VERSION 5.7 ;
  NOWIREEXTENSIONATPIN ON ;
  DIVIDERCHAR "/" ;
  BUSBITCHARS "[]" ;
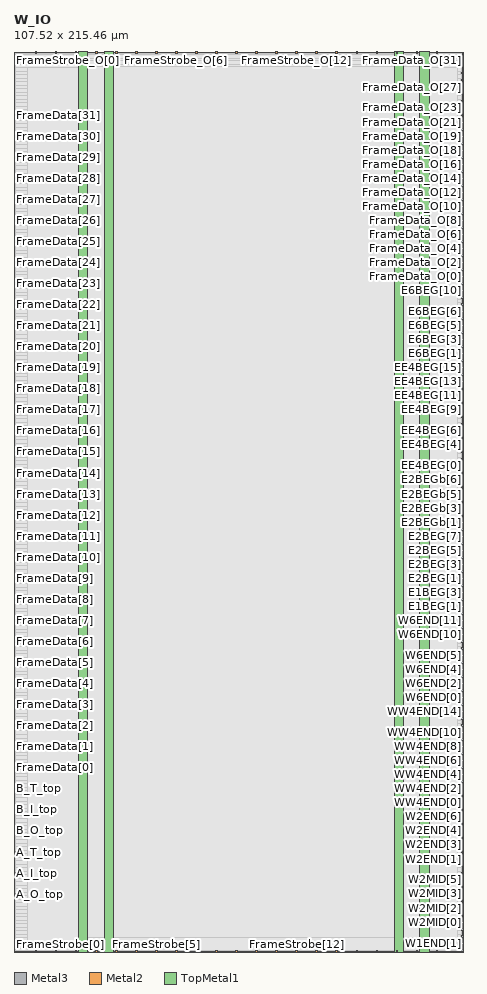
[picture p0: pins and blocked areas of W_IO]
MACRO W_IO
  CLASS BLOCK ;
  FOREIGN W_IO ;
  ORIGIN 0.000 0.000 ;
  SIZE 107.520 BY 215.460 ;
  PIN A_I_top
    DIRECTION OUTPUT ;
    USE SIGNAL ;
    ANTENNADIFFAREA 0.708600 ;
    PORT
      LAYER Metal3 ;
        RECT 0.000 18.700 0.400 19.100 ;
    END
  END A_I_top
  PIN A_O_top
    DIRECTION INPUT ;
    USE SIGNAL ;
    ANTENNAGATEAREA 0.213200 ;
    PORT
      LAYER Metal3 ;
        RECT 0.000 13.660 0.400 14.060 ;
    END
  END A_O_top
  PIN A_T_top
    DIRECTION OUTPUT ;
    USE SIGNAL ;
    ANTENNADIFFAREA 0.708600 ;
    PORT
      LAYER Metal3 ;
        RECT 0.000 23.740 0.400 24.140 ;
    END
  END A_T_top
  PIN B_I_top
    DIRECTION OUTPUT ;
    USE SIGNAL ;
    ANTENNADIFFAREA 0.708600 ;
    PORT
      LAYER Metal3 ;
        RECT 0.000 33.820 0.400 34.220 ;
    END
  END B_I_top
  PIN B_O_top
    DIRECTION INPUT ;
    USE SIGNAL ;
    ANTENNAGATEAREA 0.213200 ;
    PORT
      LAYER Metal3 ;
        RECT 0.000 28.780 0.400 29.180 ;
    END
  END B_O_top
  PIN B_T_top
    DIRECTION OUTPUT ;
    USE SIGNAL ;
    ANTENNADIFFAREA 0.708600 ;
    PORT
      LAYER Metal3 ;
        RECT 0.000 38.860 0.400 39.260 ;
    END
  END B_T_top
  PIN E1BEG[0]
    DIRECTION OUTPUT ;
    USE SIGNAL ;
    ANTENNADIFFAREA 0.708600 ;
    PORT
      LAYER Metal3 ;
        RECT 107.120 80.860 107.520 81.260 ;
    END
  END E1BEG[0]
  PIN E1BEG[1]
    DIRECTION OUTPUT ;
    USE SIGNAL ;
    ANTENNADIFFAREA 0.708600 ;
    PORT
      LAYER Metal3 ;
        RECT 107.120 82.540 107.520 82.940 ;
    END
  END E1BEG[1]
  PIN E1BEG[2]
    DIRECTION OUTPUT ;
    USE SIGNAL ;
    ANTENNADIFFAREA 0.708600 ;
    PORT
      LAYER Metal3 ;
        RECT 107.120 84.220 107.520 84.620 ;
    END
  END E1BEG[2]
  PIN E1BEG[3]
    DIRECTION OUTPUT ;
    USE SIGNAL ;
    ANTENNADIFFAREA 0.708600 ;
    PORT
      LAYER Metal3 ;
        RECT 107.120 85.900 107.520 86.300 ;
    END
  END E1BEG[3]
  PIN E2BEG[0]
    DIRECTION OUTPUT ;
    USE SIGNAL ;
    ANTENNADIFFAREA 0.708600 ;
    PORT
      LAYER Metal3 ;
        RECT 107.120 87.580 107.520 87.980 ;
    END
  END E2BEG[0]
  PIN E2BEG[1]
    DIRECTION OUTPUT ;
    USE SIGNAL ;
    ANTENNADIFFAREA 0.708600 ;
    PORT
      LAYER Metal3 ;
        RECT 107.120 89.260 107.520 89.660 ;
    END
  END E2BEG[1]
  PIN E2BEG[2]
    DIRECTION OUTPUT ;
    USE SIGNAL ;
    ANTENNADIFFAREA 0.708600 ;
    PORT
      LAYER Metal3 ;
        RECT 107.120 90.940 107.520 91.340 ;
    END
  END E2BEG[2]
  PIN E2BEG[3]
    DIRECTION OUTPUT ;
    USE SIGNAL ;
    ANTENNADIFFAREA 0.708600 ;
    PORT
      LAYER Metal3 ;
        RECT 107.120 92.620 107.520 93.020 ;
    END
  END E2BEG[3]
  PIN E2BEG[4]
    DIRECTION OUTPUT ;
    USE SIGNAL ;
    ANTENNADIFFAREA 0.708600 ;
    PORT
      LAYER Metal3 ;
        RECT 107.120 94.300 107.520 94.700 ;
    END
  END E2BEG[4]
  PIN E2BEG[5]
    DIRECTION OUTPUT ;
    USE SIGNAL ;
    ANTENNADIFFAREA 0.708600 ;
    PORT
      LAYER Metal3 ;
        RECT 107.120 95.980 107.520 96.380 ;
    END
  END E2BEG[5]
  PIN E2BEG[6]
    DIRECTION OUTPUT ;
    USE SIGNAL ;
    ANTENNADIFFAREA 0.708600 ;
    PORT
      LAYER Metal3 ;
        RECT 107.120 97.660 107.520 98.060 ;
    END
  END E2BEG[6]
  PIN E2BEG[7]
    DIRECTION OUTPUT ;
    USE SIGNAL ;
    ANTENNADIFFAREA 0.708600 ;
    PORT
      LAYER Metal3 ;
        RECT 107.120 99.340 107.520 99.740 ;
    END
  END E2BEG[7]
  PIN E2BEGb[0]
    DIRECTION OUTPUT ;
    USE SIGNAL ;
    ANTENNADIFFAREA 0.708600 ;
    PORT
      LAYER Metal3 ;
        RECT 107.120 101.020 107.520 101.420 ;
    END
  END E2BEGb[0]
  PIN E2BEGb[1]
    DIRECTION OUTPUT ;
    USE SIGNAL ;
    ANTENNADIFFAREA 0.708600 ;
    PORT
      LAYER Metal3 ;
        RECT 107.120 102.700 107.520 103.100 ;
    END
  END E2BEGb[1]
  PIN E2BEGb[2]
    DIRECTION OUTPUT ;
    USE SIGNAL ;
    ANTENNADIFFAREA 0.708600 ;
    PORT
      LAYER Metal3 ;
        RECT 107.120 104.380 107.520 104.780 ;
    END
  END E2BEGb[2]
  PIN E2BEGb[3]
    DIRECTION OUTPUT ;
    USE SIGNAL ;
    ANTENNADIFFAREA 0.708600 ;
    PORT
      LAYER Metal3 ;
        RECT 107.120 106.060 107.520 106.460 ;
    END
  END E2BEGb[3]
  PIN E2BEGb[4]
    DIRECTION OUTPUT ;
    USE SIGNAL ;
    ANTENNADIFFAREA 0.708600 ;
    PORT
      LAYER Metal3 ;
        RECT 107.120 107.740 107.520 108.140 ;
    END
  END E2BEGb[4]
  PIN E2BEGb[5]
    DIRECTION OUTPUT ;
    USE SIGNAL ;
    ANTENNADIFFAREA 0.708600 ;
    PORT
      LAYER Metal3 ;
        RECT 107.120 109.420 107.520 109.820 ;
    END
  END E2BEGb[5]
  PIN E2BEGb[6]
    DIRECTION OUTPUT ;
    USE SIGNAL ;
    ANTENNADIFFAREA 0.708600 ;
    PORT
      LAYER Metal3 ;
        RECT 107.120 111.100 107.520 111.500 ;
    END
  END E2BEGb[6]
  PIN E2BEGb[7]
    DIRECTION OUTPUT ;
    USE SIGNAL ;
    ANTENNADIFFAREA 0.708600 ;
    PORT
      LAYER Metal3 ;
        RECT 107.120 112.780 107.520 113.180 ;
    END
  END E2BEGb[7]
  PIN E6BEG[0]
    DIRECTION OUTPUT ;
    USE SIGNAL ;
    ANTENNADIFFAREA 0.708600 ;
    PORT
      LAYER Metal3 ;
        RECT 107.120 141.340 107.520 141.740 ;
    END
  END E6BEG[0]
  PIN E6BEG[10]
    DIRECTION OUTPUT ;
    USE SIGNAL ;
    ANTENNADIFFAREA 0.708600 ;
    PORT
      LAYER Metal3 ;
        RECT 107.120 158.140 107.520 158.540 ;
    END
  END E6BEG[10]
  PIN E6BEG[11]
    DIRECTION OUTPUT ;
    USE SIGNAL ;
    ANTENNADIFFAREA 0.708600 ;
    PORT
      LAYER Metal3 ;
        RECT 107.120 159.820 107.520 160.220 ;
    END
  END E6BEG[11]
  PIN E6BEG[1]
    DIRECTION OUTPUT ;
    USE SIGNAL ;
    ANTENNADIFFAREA 0.708600 ;
    PORT
      LAYER Metal3 ;
        RECT 107.120 143.020 107.520 143.420 ;
    END
  END E6BEG[1]
  PIN E6BEG[2]
    DIRECTION OUTPUT ;
    USE SIGNAL ;
    ANTENNADIFFAREA 0.708600 ;
    PORT
      LAYER Metal3 ;
        RECT 107.120 144.700 107.520 145.100 ;
    END
  END E6BEG[2]
  PIN E6BEG[3]
    DIRECTION OUTPUT ;
    USE SIGNAL ;
    ANTENNADIFFAREA 0.708600 ;
    PORT
      LAYER Metal3 ;
        RECT 107.120 146.380 107.520 146.780 ;
    END
  END E6BEG[3]
  PIN E6BEG[4]
    DIRECTION OUTPUT ;
    USE SIGNAL ;
    ANTENNADIFFAREA 0.708600 ;
    PORT
      LAYER Metal3 ;
        RECT 107.120 148.060 107.520 148.460 ;
    END
  END E6BEG[4]
  PIN E6BEG[5]
    DIRECTION OUTPUT ;
    USE SIGNAL ;
    ANTENNADIFFAREA 0.708600 ;
    PORT
      LAYER Metal3 ;
        RECT 107.120 149.740 107.520 150.140 ;
    END
  END E6BEG[5]
  PIN E6BEG[6]
    DIRECTION OUTPUT ;
    USE SIGNAL ;
    ANTENNADIFFAREA 0.708600 ;
    PORT
      LAYER Metal3 ;
        RECT 107.120 151.420 107.520 151.820 ;
    END
  END E6BEG[6]
  PIN E6BEG[7]
    DIRECTION OUTPUT ;
    USE SIGNAL ;
    ANTENNADIFFAREA 0.708600 ;
    PORT
      LAYER Metal3 ;
        RECT 107.120 153.100 107.520 153.500 ;
    END
  END E6BEG[7]
  PIN E6BEG[8]
    DIRECTION OUTPUT ;
    USE SIGNAL ;
    ANTENNADIFFAREA 0.708600 ;
    PORT
      LAYER Metal3 ;
        RECT 107.120 154.780 107.520 155.180 ;
    END
  END E6BEG[8]
  PIN E6BEG[9]
    DIRECTION OUTPUT ;
    USE SIGNAL ;
    ANTENNADIFFAREA 0.708600 ;
    PORT
      LAYER Metal3 ;
        RECT 107.120 156.460 107.520 156.860 ;
    END
  END E6BEG[9]
  PIN EE4BEG[0]
    DIRECTION OUTPUT ;
    USE SIGNAL ;
    ANTENNADIFFAREA 0.708600 ;
    PORT
      LAYER Metal3 ;
        RECT 107.120 114.460 107.520 114.860 ;
    END
  END EE4BEG[0]
  PIN EE4BEG[10]
    DIRECTION OUTPUT ;
    USE SIGNAL ;
    ANTENNADIFFAREA 0.708600 ;
    PORT
      LAYER Metal3 ;
        RECT 107.120 131.260 107.520 131.660 ;
    END
  END EE4BEG[10]
  PIN EE4BEG[11]
    DIRECTION OUTPUT ;
    USE SIGNAL ;
    ANTENNADIFFAREA 0.708600 ;
    PORT
      LAYER Metal3 ;
        RECT 107.120 132.940 107.520 133.340 ;
    END
  END EE4BEG[11]
  PIN EE4BEG[12]
    DIRECTION OUTPUT ;
    USE SIGNAL ;
    ANTENNADIFFAREA 0.708600 ;
    PORT
      LAYER Metal3 ;
        RECT 107.120 134.620 107.520 135.020 ;
    END
  END EE4BEG[12]
  PIN EE4BEG[13]
    DIRECTION OUTPUT ;
    USE SIGNAL ;
    ANTENNADIFFAREA 0.708600 ;
    PORT
      LAYER Metal3 ;
        RECT 107.120 136.300 107.520 136.700 ;
    END
  END EE4BEG[13]
  PIN EE4BEG[14]
    DIRECTION OUTPUT ;
    USE SIGNAL ;
    ANTENNADIFFAREA 0.708600 ;
    PORT
      LAYER Metal3 ;
        RECT 107.120 137.980 107.520 138.380 ;
    END
  END EE4BEG[14]
  PIN EE4BEG[15]
    DIRECTION OUTPUT ;
    USE SIGNAL ;
    ANTENNADIFFAREA 0.708600 ;
    PORT
      LAYER Metal3 ;
        RECT 107.120 139.660 107.520 140.060 ;
    END
  END EE4BEG[15]
  PIN EE4BEG[1]
    DIRECTION OUTPUT ;
    USE SIGNAL ;
    ANTENNADIFFAREA 0.708600 ;
    PORT
      LAYER Metal3 ;
        RECT 107.120 116.140 107.520 116.540 ;
    END
  END EE4BEG[1]
  PIN EE4BEG[2]
    DIRECTION OUTPUT ;
    USE SIGNAL ;
    ANTENNADIFFAREA 0.708600 ;
    PORT
      LAYER Metal3 ;
        RECT 107.120 117.820 107.520 118.220 ;
    END
  END EE4BEG[2]
  PIN EE4BEG[3]
    DIRECTION OUTPUT ;
    USE SIGNAL ;
    ANTENNADIFFAREA 0.708600 ;
    PORT
      LAYER Metal3 ;
        RECT 107.120 119.500 107.520 119.900 ;
    END
  END EE4BEG[3]
  PIN EE4BEG[4]
    DIRECTION OUTPUT ;
    USE SIGNAL ;
    ANTENNADIFFAREA 0.708600 ;
    PORT
      LAYER Metal3 ;
        RECT 107.120 121.180 107.520 121.580 ;
    END
  END EE4BEG[4]
  PIN EE4BEG[5]
    DIRECTION OUTPUT ;
    USE SIGNAL ;
    ANTENNADIFFAREA 0.708600 ;
    PORT
      LAYER Metal3 ;
        RECT 107.120 122.860 107.520 123.260 ;
    END
  END EE4BEG[5]
  PIN EE4BEG[6]
    DIRECTION OUTPUT ;
    USE SIGNAL ;
    ANTENNADIFFAREA 0.708600 ;
    PORT
      LAYER Metal3 ;
        RECT 107.120 124.540 107.520 124.940 ;
    END
  END EE4BEG[6]
  PIN EE4BEG[7]
    DIRECTION OUTPUT ;
    USE SIGNAL ;
    ANTENNADIFFAREA 0.708600 ;
    PORT
      LAYER Metal3 ;
        RECT 107.120 126.220 107.520 126.620 ;
    END
  END EE4BEG[7]
  PIN EE4BEG[8]
    DIRECTION OUTPUT ;
    USE SIGNAL ;
    ANTENNADIFFAREA 0.708600 ;
    PORT
      LAYER Metal3 ;
        RECT 107.120 127.900 107.520 128.300 ;
    END
  END EE4BEG[8]
  PIN EE4BEG[9]
    DIRECTION OUTPUT ;
    USE SIGNAL ;
    ANTENNADIFFAREA 0.708600 ;
    PORT
      LAYER Metal3 ;
        RECT 107.120 129.580 107.520 129.980 ;
    END
  END EE4BEG[9]
  PIN FrameData[0]
    DIRECTION INPUT ;
    USE SIGNAL ;
    ANTENNAGATEAREA 0.180700 ;
    PORT
      LAYER Metal3 ;
        RECT 0.000 43.900 0.400 44.300 ;
    END
  END FrameData[0]
  PIN FrameData[10]
    DIRECTION INPUT ;
    USE SIGNAL ;
    ANTENNAGATEAREA 0.180700 ;
    PORT
      LAYER Metal3 ;
        RECT 0.000 94.300 0.400 94.700 ;
    END
  END FrameData[10]
  PIN FrameData[11]
    DIRECTION INPUT ;
    USE SIGNAL ;
    ANTENNAGATEAREA 0.180700 ;
    PORT
      LAYER Metal3 ;
        RECT 0.000 99.340 0.400 99.740 ;
    END
  END FrameData[11]
  PIN FrameData[12]
    DIRECTION INPUT ;
    USE SIGNAL ;
    ANTENNAGATEAREA 0.180700 ;
    PORT
      LAYER Metal3 ;
        RECT 0.000 104.380 0.400 104.780 ;
    END
  END FrameData[12]
  PIN FrameData[13]
    DIRECTION INPUT ;
    USE SIGNAL ;
    ANTENNAGATEAREA 0.180700 ;
    PORT
      LAYER Metal3 ;
        RECT 0.000 109.420 0.400 109.820 ;
    END
  END FrameData[13]
  PIN FrameData[14]
    DIRECTION INPUT ;
    USE SIGNAL ;
    ANTENNAGATEAREA 0.180700 ;
    PORT
      LAYER Metal3 ;
        RECT 0.000 114.460 0.400 114.860 ;
    END
  END FrameData[14]
  PIN FrameData[15]
    DIRECTION INPUT ;
    USE SIGNAL ;
    ANTENNAGATEAREA 0.180700 ;
    PORT
      LAYER Metal3 ;
        RECT 0.000 119.500 0.400 119.900 ;
    END
  END FrameData[15]
  PIN FrameData[16]
    DIRECTION INPUT ;
    USE SIGNAL ;
    ANTENNAGATEAREA 0.180700 ;
    PORT
      LAYER Metal3 ;
        RECT 0.000 124.540 0.400 124.940 ;
    END
  END FrameData[16]
  PIN FrameData[17]
    DIRECTION INPUT ;
    USE SIGNAL ;
    ANTENNAGATEAREA 0.180700 ;
    PORT
      LAYER Metal3 ;
        RECT 0.000 129.580 0.400 129.980 ;
    END
  END FrameData[17]
  PIN FrameData[18]
    DIRECTION INPUT ;
    USE SIGNAL ;
    ANTENNAGATEAREA 0.180700 ;
    PORT
      LAYER Metal3 ;
        RECT 0.000 134.620 0.400 135.020 ;
    END
  END FrameData[18]
  PIN FrameData[19]
    DIRECTION INPUT ;
    USE SIGNAL ;
    ANTENNAGATEAREA 0.180700 ;
    PORT
      LAYER Metal3 ;
        RECT 0.000 139.660 0.400 140.060 ;
    END
  END FrameData[19]
  PIN FrameData[1]
    DIRECTION INPUT ;
    USE SIGNAL ;
    ANTENNAGATEAREA 0.180700 ;
    PORT
      LAYER Metal3 ;
        RECT 0.000 48.940 0.400 49.340 ;
    END
  END FrameData[1]
  PIN FrameData[20]
    DIRECTION INPUT ;
    USE SIGNAL ;
    ANTENNAGATEAREA 0.180700 ;
    PORT
      LAYER Metal3 ;
        RECT 0.000 144.700 0.400 145.100 ;
    END
  END FrameData[20]
  PIN FrameData[21]
    DIRECTION INPUT ;
    USE SIGNAL ;
    ANTENNAGATEAREA 0.180700 ;
    PORT
      LAYER Metal3 ;
        RECT 0.000 149.740 0.400 150.140 ;
    END
  END FrameData[21]
  PIN FrameData[22]
    DIRECTION INPUT ;
    USE SIGNAL ;
    ANTENNAGATEAREA 0.213200 ;
    PORT
      LAYER Metal3 ;
        RECT 0.000 154.780 0.400 155.180 ;
    END
  END FrameData[22]
  PIN FrameData[23]
    DIRECTION INPUT ;
    USE SIGNAL ;
    ANTENNAGATEAREA 0.213200 ;
    PORT
      LAYER Metal3 ;
        RECT 0.000 159.820 0.400 160.220 ;
    END
  END FrameData[23]
  PIN FrameData[24]
    DIRECTION INPUT ;
    USE SIGNAL ;
    ANTENNAGATEAREA 0.213200 ;
    PORT
      LAYER Metal3 ;
        RECT 0.000 164.860 0.400 165.260 ;
    END
  END FrameData[24]
  PIN FrameData[25]
    DIRECTION INPUT ;
    USE SIGNAL ;
    ANTENNAGATEAREA 0.213200 ;
    PORT
      LAYER Metal3 ;
        RECT 0.000 169.900 0.400 170.300 ;
    END
  END FrameData[25]
  PIN FrameData[26]
    DIRECTION INPUT ;
    USE SIGNAL ;
    ANTENNAGATEAREA 0.213200 ;
    PORT
      LAYER Metal3 ;
        RECT 0.000 174.940 0.400 175.340 ;
    END
  END FrameData[26]
  PIN FrameData[27]
    DIRECTION INPUT ;
    USE SIGNAL ;
    ANTENNAGATEAREA 0.213200 ;
    PORT
      LAYER Metal3 ;
        RECT 0.000 179.980 0.400 180.380 ;
    END
  END FrameData[27]
  PIN FrameData[28]
    DIRECTION INPUT ;
    USE SIGNAL ;
    ANTENNAGATEAREA 0.213200 ;
    PORT
      LAYER Metal3 ;
        RECT 0.000 185.020 0.400 185.420 ;
    END
  END FrameData[28]
  PIN FrameData[29]
    DIRECTION INPUT ;
    USE SIGNAL ;
    ANTENNAGATEAREA 0.213200 ;
    PORT
      LAYER Metal3 ;
        RECT 0.000 190.060 0.400 190.460 ;
    END
  END FrameData[29]
  PIN FrameData[2]
    DIRECTION INPUT ;
    USE SIGNAL ;
    ANTENNAGATEAREA 0.180700 ;
    PORT
      LAYER Metal3 ;
        RECT 0.000 53.980 0.400 54.380 ;
    END
  END FrameData[2]
  PIN FrameData[30]
    DIRECTION INPUT ;
    USE SIGNAL ;
    ANTENNAGATEAREA 0.213200 ;
    PORT
      LAYER Metal3 ;
        RECT 0.000 195.100 0.400 195.500 ;
    END
  END FrameData[30]
  PIN FrameData[31]
    DIRECTION INPUT ;
    USE SIGNAL ;
    ANTENNAGATEAREA 0.213200 ;
    PORT
      LAYER Metal3 ;
        RECT 0.000 200.140 0.400 200.540 ;
    END
  END FrameData[31]
  PIN FrameData[3]
    DIRECTION INPUT ;
    USE SIGNAL ;
    ANTENNAGATEAREA 0.180700 ;
    PORT
      LAYER Metal3 ;
        RECT 0.000 59.020 0.400 59.420 ;
    END
  END FrameData[3]
  PIN FrameData[4]
    DIRECTION INPUT ;
    USE SIGNAL ;
    ANTENNAGATEAREA 0.180700 ;
    PORT
      LAYER Metal3 ;
        RECT 0.000 64.060 0.400 64.460 ;
    END
  END FrameData[4]
  PIN FrameData[5]
    DIRECTION INPUT ;
    USE SIGNAL ;
    ANTENNAGATEAREA 0.180700 ;
    PORT
      LAYER Metal3 ;
        RECT 0.000 69.100 0.400 69.500 ;
    END
  END FrameData[5]
  PIN FrameData[6]
    DIRECTION INPUT ;
    USE SIGNAL ;
    ANTENNAGATEAREA 0.180700 ;
    PORT
      LAYER Metal3 ;
        RECT 0.000 74.140 0.400 74.540 ;
    END
  END FrameData[6]
  PIN FrameData[7]
    DIRECTION INPUT ;
    USE SIGNAL ;
    ANTENNAGATEAREA 0.180700 ;
    PORT
      LAYER Metal3 ;
        RECT 0.000 79.180 0.400 79.580 ;
    END
  END FrameData[7]
  PIN FrameData[8]
    DIRECTION INPUT ;
    USE SIGNAL ;
    ANTENNAGATEAREA 0.180700 ;
    PORT
      LAYER Metal3 ;
        RECT 0.000 84.220 0.400 84.620 ;
    END
  END FrameData[8]
  PIN FrameData[9]
    DIRECTION INPUT ;
    USE SIGNAL ;
    ANTENNAGATEAREA 0.180700 ;
    PORT
      LAYER Metal3 ;
        RECT 0.000 89.260 0.400 89.660 ;
    END
  END FrameData[9]
  PIN FrameData_O[0]
    DIRECTION OUTPUT ;
    USE SIGNAL ;
    ANTENNADIFFAREA 0.708600 ;
    PORT
      LAYER Metal3 ;
        RECT 107.120 161.500 107.520 161.900 ;
    END
  END FrameData_O[0]
  PIN FrameData_O[10]
    DIRECTION OUTPUT ;
    USE SIGNAL ;
    ANTENNADIFFAREA 0.708600 ;
    PORT
      LAYER Metal3 ;
        RECT 107.120 178.300 107.520 178.700 ;
    END
  END FrameData_O[10]
  PIN FrameData_O[11]
    DIRECTION OUTPUT ;
    USE SIGNAL ;
    ANTENNADIFFAREA 0.708600 ;
    PORT
      LAYER Metal3 ;
        RECT 107.120 179.980 107.520 180.380 ;
    END
  END FrameData_O[11]
  PIN FrameData_O[12]
    DIRECTION OUTPUT ;
    USE SIGNAL ;
    ANTENNADIFFAREA 0.708600 ;
    PORT
      LAYER Metal3 ;
        RECT 107.120 181.660 107.520 182.060 ;
    END
  END FrameData_O[12]
  PIN FrameData_O[13]
    DIRECTION OUTPUT ;
    USE SIGNAL ;
    ANTENNADIFFAREA 0.708600 ;
    PORT
      LAYER Metal3 ;
        RECT 107.120 183.340 107.520 183.740 ;
    END
  END FrameData_O[13]
  PIN FrameData_O[14]
    DIRECTION OUTPUT ;
    USE SIGNAL ;
    ANTENNADIFFAREA 0.708600 ;
    PORT
      LAYER Metal3 ;
        RECT 107.120 185.020 107.520 185.420 ;
    END
  END FrameData_O[14]
  PIN FrameData_O[15]
    DIRECTION OUTPUT ;
    USE SIGNAL ;
    ANTENNADIFFAREA 0.708600 ;
    PORT
      LAYER Metal3 ;
        RECT 107.120 186.700 107.520 187.100 ;
    END
  END FrameData_O[15]
  PIN FrameData_O[16]
    DIRECTION OUTPUT ;
    USE SIGNAL ;
    ANTENNADIFFAREA 0.708600 ;
    PORT
      LAYER Metal3 ;
        RECT 107.120 188.380 107.520 188.780 ;
    END
  END FrameData_O[16]
  PIN FrameData_O[17]
    DIRECTION OUTPUT ;
    USE SIGNAL ;
    ANTENNADIFFAREA 0.708600 ;
    PORT
      LAYER Metal3 ;
        RECT 107.120 190.060 107.520 190.460 ;
    END
  END FrameData_O[17]
  PIN FrameData_O[18]
    DIRECTION OUTPUT ;
    USE SIGNAL ;
    ANTENNADIFFAREA 0.708600 ;
    PORT
      LAYER Metal3 ;
        RECT 107.120 191.740 107.520 192.140 ;
    END
  END FrameData_O[18]
  PIN FrameData_O[19]
    DIRECTION OUTPUT ;
    USE SIGNAL ;
    ANTENNADIFFAREA 0.708600 ;
    PORT
      LAYER Metal3 ;
        RECT 107.120 193.420 107.520 193.820 ;
    END
  END FrameData_O[19]
  PIN FrameData_O[1]
    DIRECTION OUTPUT ;
    USE SIGNAL ;
    ANTENNADIFFAREA 0.708600 ;
    PORT
      LAYER Metal3 ;
        RECT 107.120 163.180 107.520 163.580 ;
    END
  END FrameData_O[1]
  PIN FrameData_O[20]
    DIRECTION OUTPUT ;
    USE SIGNAL ;
    ANTENNADIFFAREA 0.708600 ;
    PORT
      LAYER Metal3 ;
        RECT 107.120 195.100 107.520 195.500 ;
    END
  END FrameData_O[20]
  PIN FrameData_O[21]
    DIRECTION OUTPUT ;
    USE SIGNAL ;
    ANTENNADIFFAREA 0.708600 ;
    PORT
      LAYER Metal3 ;
        RECT 107.120 196.780 107.520 197.180 ;
    END
  END FrameData_O[21]
  PIN FrameData_O[22]
    DIRECTION OUTPUT ;
    USE SIGNAL ;
    ANTENNADIFFAREA 0.708600 ;
    PORT
      LAYER Metal3 ;
        RECT 107.120 198.460 107.520 198.860 ;
    END
  END FrameData_O[22]
  PIN FrameData_O[23]
    DIRECTION OUTPUT ;
    USE SIGNAL ;
    ANTENNADIFFAREA 0.708600 ;
    PORT
      LAYER Metal3 ;
        RECT 107.120 200.140 107.520 200.540 ;
    END
  END FrameData_O[23]
  PIN FrameData_O[24]
    DIRECTION OUTPUT ;
    USE SIGNAL ;
    ANTENNADIFFAREA 0.708600 ;
    PORT
      LAYER Metal3 ;
        RECT 107.120 201.820 107.520 202.220 ;
    END
  END FrameData_O[24]
  PIN FrameData_O[25]
    DIRECTION OUTPUT ;
    USE SIGNAL ;
    ANTENNADIFFAREA 0.708600 ;
    PORT
      LAYER Metal3 ;
        RECT 107.120 203.500 107.520 203.900 ;
    END
  END FrameData_O[25]
  PIN FrameData_O[26]
    DIRECTION OUTPUT ;
    USE SIGNAL ;
    ANTENNADIFFAREA 0.708600 ;
    PORT
      LAYER Metal3 ;
        RECT 107.120 205.180 107.520 205.580 ;
    END
  END FrameData_O[26]
  PIN FrameData_O[27]
    DIRECTION OUTPUT ;
    USE SIGNAL ;
    ANTENNADIFFAREA 0.708600 ;
    PORT
      LAYER Metal3 ;
        RECT 107.120 206.860 107.520 207.260 ;
    END
  END FrameData_O[27]
  PIN FrameData_O[28]
    DIRECTION OUTPUT ;
    USE SIGNAL ;
    ANTENNADIFFAREA 0.708600 ;
    PORT
      LAYER Metal3 ;
        RECT 107.120 208.540 107.520 208.940 ;
    END
  END FrameData_O[28]
  PIN FrameData_O[29]
    DIRECTION OUTPUT ;
    USE SIGNAL ;
    ANTENNADIFFAREA 0.708600 ;
    PORT
      LAYER Metal3 ;
        RECT 107.120 210.220 107.520 210.620 ;
    END
  END FrameData_O[29]
  PIN FrameData_O[2]
    DIRECTION OUTPUT ;
    USE SIGNAL ;
    ANTENNADIFFAREA 0.708600 ;
    PORT
      LAYER Metal3 ;
        RECT 107.120 164.860 107.520 165.260 ;
    END
  END FrameData_O[2]
  PIN FrameData_O[30]
    DIRECTION OUTPUT ;
    USE SIGNAL ;
    ANTENNADIFFAREA 0.708600 ;
    PORT
      LAYER Metal3 ;
        RECT 107.120 211.900 107.520 212.300 ;
    END
  END FrameData_O[30]
  PIN FrameData_O[31]
    DIRECTION OUTPUT ;
    USE SIGNAL ;
    ANTENNADIFFAREA 0.708600 ;
    PORT
      LAYER Metal3 ;
        RECT 107.120 213.580 107.520 213.980 ;
    END
  END FrameData_O[31]
  PIN FrameData_O[3]
    DIRECTION OUTPUT ;
    USE SIGNAL ;
    ANTENNADIFFAREA 0.708600 ;
    PORT
      LAYER Metal3 ;
        RECT 107.120 166.540 107.520 166.940 ;
    END
  END FrameData_O[3]
  PIN FrameData_O[4]
    DIRECTION OUTPUT ;
    USE SIGNAL ;
    ANTENNADIFFAREA 0.708600 ;
    PORT
      LAYER Metal3 ;
        RECT 107.120 168.220 107.520 168.620 ;
    END
  END FrameData_O[4]
  PIN FrameData_O[5]
    DIRECTION OUTPUT ;
    USE SIGNAL ;
    ANTENNADIFFAREA 0.708600 ;
    PORT
      LAYER Metal3 ;
        RECT 107.120 169.900 107.520 170.300 ;
    END
  END FrameData_O[5]
  PIN FrameData_O[6]
    DIRECTION OUTPUT ;
    USE SIGNAL ;
    ANTENNADIFFAREA 0.708600 ;
    PORT
      LAYER Metal3 ;
        RECT 107.120 171.580 107.520 171.980 ;
    END
  END FrameData_O[6]
  PIN FrameData_O[7]
    DIRECTION OUTPUT ;
    USE SIGNAL ;
    ANTENNADIFFAREA 0.708600 ;
    PORT
      LAYER Metal3 ;
        RECT 107.120 173.260 107.520 173.660 ;
    END
  END FrameData_O[7]
  PIN FrameData_O[8]
    DIRECTION OUTPUT ;
    USE SIGNAL ;
    ANTENNADIFFAREA 0.708600 ;
    PORT
      LAYER Metal3 ;
        RECT 107.120 174.940 107.520 175.340 ;
    END
  END FrameData_O[8]
  PIN FrameData_O[9]
    DIRECTION OUTPUT ;
    USE SIGNAL ;
    ANTENNADIFFAREA 0.708600 ;
    PORT
      LAYER Metal3 ;
        RECT 107.120 176.620 107.520 177.020 ;
    END
  END FrameData_O[9]
  PIN FrameStrobe[0]
    DIRECTION INPUT ;
    USE SIGNAL ;
    ANTENNAGATEAREA 0.213200 ;
    PORT
      LAYER Metal2 ;
        RECT 9.880 0.000 10.280 0.400 ;
    END
  END FrameStrobe[0]
  PIN FrameStrobe[10]
    DIRECTION INPUT ;
    USE SIGNAL ;
    ANTENNAGATEAREA 0.180700 ;
    PORT
      LAYER Metal2 ;
        RECT 57.880 0.000 58.280 0.400 ;
    END
  END FrameStrobe[10]
  PIN FrameStrobe[11]
    DIRECTION INPUT ;
    USE SIGNAL ;
    ANTENNAGATEAREA 0.180700 ;
    PORT
      LAYER Metal2 ;
        RECT 62.680 0.000 63.080 0.400 ;
    END
  END FrameStrobe[11]
  PIN FrameStrobe[12]
    DIRECTION INPUT ;
    USE SIGNAL ;
    ANTENNAGATEAREA 0.180700 ;
    PORT
      LAYER Metal2 ;
        RECT 67.480 0.000 67.880 0.400 ;
    END
  END FrameStrobe[12]
  PIN FrameStrobe[13]
    DIRECTION INPUT ;
    USE SIGNAL ;
    ANTENNAGATEAREA 0.180700 ;
    PORT
      LAYER Metal2 ;
        RECT 72.280 0.000 72.680 0.400 ;
    END
  END FrameStrobe[13]
  PIN FrameStrobe[14]
    DIRECTION INPUT ;
    USE SIGNAL ;
    ANTENNAGATEAREA 0.180700 ;
    PORT
      LAYER Metal2 ;
        RECT 77.080 0.000 77.480 0.400 ;
    END
  END FrameStrobe[14]
  PIN FrameStrobe[15]
    DIRECTION INPUT ;
    USE SIGNAL ;
    ANTENNAGATEAREA 0.180700 ;
    PORT
      LAYER Metal2 ;
        RECT 81.880 0.000 82.280 0.400 ;
    END
  END FrameStrobe[15]
  PIN FrameStrobe[16]
    DIRECTION INPUT ;
    USE SIGNAL ;
    ANTENNAGATEAREA 0.180700 ;
    PORT
      LAYER Metal2 ;
        RECT 86.680 0.000 87.080 0.400 ;
    END
  END FrameStrobe[16]
  PIN FrameStrobe[17]
    DIRECTION INPUT ;
    USE SIGNAL ;
    ANTENNAGATEAREA 0.180700 ;
    PORT
      LAYER Metal2 ;
        RECT 91.480 0.000 91.880 0.400 ;
    END
  END FrameStrobe[17]
  PIN FrameStrobe[18]
    DIRECTION INPUT ;
    USE SIGNAL ;
    ANTENNAGATEAREA 0.180700 ;
    PORT
      LAYER Metal2 ;
        RECT 96.280 0.000 96.680 0.400 ;
    END
  END FrameStrobe[18]
  PIN FrameStrobe[19]
    DIRECTION INPUT ;
    USE SIGNAL ;
    ANTENNAGATEAREA 0.180700 ;
    PORT
      LAYER Metal2 ;
        RECT 101.080 0.000 101.480 0.400 ;
    END
  END FrameStrobe[19]
  PIN FrameStrobe[1]
    DIRECTION INPUT ;
    USE SIGNAL ;
    ANTENNAGATEAREA 0.938600 ;
    PORT
      LAYER Metal2 ;
        RECT 14.680 0.000 15.080 0.400 ;
    END
  END FrameStrobe[1]
  PIN FrameStrobe[2]
    DIRECTION INPUT ;
    USE SIGNAL ;
    ANTENNAGATEAREA 0.180700 ;
    PORT
      LAYER Metal2 ;
        RECT 19.480 0.000 19.880 0.400 ;
    END
  END FrameStrobe[2]
  PIN FrameStrobe[3]
    DIRECTION INPUT ;
    USE SIGNAL ;
    ANTENNAGATEAREA 0.213200 ;
    PORT
      LAYER Metal2 ;
        RECT 24.280 0.000 24.680 0.400 ;
    END
  END FrameStrobe[3]
  PIN FrameStrobe[4]
    DIRECTION INPUT ;
    USE SIGNAL ;
    ANTENNAGATEAREA 0.180700 ;
    PORT
      LAYER Metal2 ;
        RECT 29.080 0.000 29.480 0.400 ;
    END
  END FrameStrobe[4]
  PIN FrameStrobe[5]
    DIRECTION INPUT ;
    USE SIGNAL ;
    ANTENNAGATEAREA 0.725400 ;
    PORT
      LAYER Metal2 ;
        RECT 33.880 0.000 34.280 0.400 ;
    END
  END FrameStrobe[5]
  PIN FrameStrobe[6]
    DIRECTION INPUT ;
    USE SIGNAL ;
    ANTENNAGATEAREA 0.180700 ;
    PORT
      LAYER Metal2 ;
        RECT 38.680 0.000 39.080 0.400 ;
    END
  END FrameStrobe[6]
  PIN FrameStrobe[7]
    DIRECTION INPUT ;
    USE SIGNAL ;
    ANTENNAGATEAREA 0.180700 ;
    PORT
      LAYER Metal2 ;
        RECT 43.480 0.000 43.880 0.400 ;
    END
  END FrameStrobe[7]
  PIN FrameStrobe[8]
    DIRECTION INPUT ;
    USE SIGNAL ;
    ANTENNAGATEAREA 0.213200 ;
    PORT
      LAYER Metal2 ;
        RECT 48.280 0.000 48.680 0.400 ;
    END
  END FrameStrobe[8]
  PIN FrameStrobe[9]
    DIRECTION INPUT ;
    USE SIGNAL ;
    ANTENNAGATEAREA 0.180700 ;
    PORT
      LAYER Metal2 ;
        RECT 53.080 0.000 53.480 0.400 ;
    END
  END FrameStrobe[9]
  PIN FrameStrobe_O[0]
    DIRECTION OUTPUT ;
    USE SIGNAL ;
    ANTENNADIFFAREA 0.708600 ;
    PORT
      LAYER Metal2 ;
        RECT 9.880 215.060 10.280 215.460 ;
    END
  END FrameStrobe_O[0]
  PIN FrameStrobe_O[10]
    DIRECTION OUTPUT ;
    USE SIGNAL ;
    ANTENNADIFFAREA 0.708600 ;
    PORT
      LAYER Metal2 ;
        RECT 57.880 215.060 58.280 215.460 ;
    END
  END FrameStrobe_O[10]
  PIN FrameStrobe_O[11]
    DIRECTION OUTPUT ;
    USE SIGNAL ;
    ANTENNADIFFAREA 0.708600 ;
    PORT
      LAYER Metal2 ;
        RECT 62.680 215.060 63.080 215.460 ;
    END
  END FrameStrobe_O[11]
  PIN FrameStrobe_O[12]
    DIRECTION OUTPUT ;
    USE SIGNAL ;
    ANTENNADIFFAREA 0.708600 ;
    PORT
      LAYER Metal2 ;
        RECT 67.480 215.060 67.880 215.460 ;
    END
  END FrameStrobe_O[12]
  PIN FrameStrobe_O[13]
    DIRECTION OUTPUT ;
    USE SIGNAL ;
    ANTENNADIFFAREA 0.708600 ;
    PORT
      LAYER Metal2 ;
        RECT 72.280 215.060 72.680 215.460 ;
    END
  END FrameStrobe_O[13]
  PIN FrameStrobe_O[14]
    DIRECTION OUTPUT ;
    USE SIGNAL ;
    ANTENNADIFFAREA 0.708600 ;
    PORT
      LAYER Metal2 ;
        RECT 77.080 215.060 77.480 215.460 ;
    END
  END FrameStrobe_O[14]
  PIN FrameStrobe_O[15]
    DIRECTION OUTPUT ;
    USE SIGNAL ;
    ANTENNADIFFAREA 0.708600 ;
    PORT
      LAYER Metal2 ;
        RECT 81.880 215.060 82.280 215.460 ;
    END
  END FrameStrobe_O[15]
  PIN FrameStrobe_O[16]
    DIRECTION OUTPUT ;
    USE SIGNAL ;
    ANTENNADIFFAREA 0.708600 ;
    PORT
      LAYER Metal2 ;
        RECT 86.680 215.060 87.080 215.460 ;
    END
  END FrameStrobe_O[16]
  PIN FrameStrobe_O[17]
    DIRECTION OUTPUT ;
    USE SIGNAL ;
    ANTENNADIFFAREA 0.708600 ;
    PORT
      LAYER Metal2 ;
        RECT 91.480 215.060 91.880 215.460 ;
    END
  END FrameStrobe_O[17]
  PIN FrameStrobe_O[18]
    DIRECTION OUTPUT ;
    USE SIGNAL ;
    ANTENNADIFFAREA 0.708600 ;
    PORT
      LAYER Metal2 ;
        RECT 96.280 215.060 96.680 215.460 ;
    END
  END FrameStrobe_O[18]
  PIN FrameStrobe_O[19]
    DIRECTION OUTPUT ;
    USE SIGNAL ;
    ANTENNADIFFAREA 0.708600 ;
    PORT
      LAYER Metal2 ;
        RECT 101.080 215.060 101.480 215.460 ;
    END
  END FrameStrobe_O[19]
  PIN FrameStrobe_O[1]
    DIRECTION OUTPUT ;
    USE SIGNAL ;
    ANTENNADIFFAREA 0.708600 ;
    PORT
      LAYER Metal2 ;
        RECT 14.680 215.060 15.080 215.460 ;
    END
  END FrameStrobe_O[1]
  PIN FrameStrobe_O[2]
    DIRECTION OUTPUT ;
    USE SIGNAL ;
    ANTENNADIFFAREA 0.708600 ;
    PORT
      LAYER Metal2 ;
        RECT 19.480 215.060 19.880 215.460 ;
    END
  END FrameStrobe_O[2]
  PIN FrameStrobe_O[3]
    DIRECTION OUTPUT ;
    USE SIGNAL ;
    ANTENNADIFFAREA 0.708600 ;
    PORT
      LAYER Metal2 ;
        RECT 24.280 215.060 24.680 215.460 ;
    END
  END FrameStrobe_O[3]
  PIN FrameStrobe_O[4]
    DIRECTION OUTPUT ;
    USE SIGNAL ;
    ANTENNADIFFAREA 0.708600 ;
    PORT
      LAYER Metal2 ;
        RECT 29.080 215.060 29.480 215.460 ;
    END
  END FrameStrobe_O[4]
  PIN FrameStrobe_O[5]
    DIRECTION OUTPUT ;
    USE SIGNAL ;
    ANTENNADIFFAREA 0.708600 ;
    PORT
      LAYER Metal2 ;
        RECT 33.880 215.060 34.280 215.460 ;
    END
  END FrameStrobe_O[5]
  PIN FrameStrobe_O[6]
    DIRECTION OUTPUT ;
    USE SIGNAL ;
    ANTENNADIFFAREA 0.708600 ;
    PORT
      LAYER Metal2 ;
        RECT 38.680 215.060 39.080 215.460 ;
    END
  END FrameStrobe_O[6]
  PIN FrameStrobe_O[7]
    DIRECTION OUTPUT ;
    USE SIGNAL ;
    ANTENNADIFFAREA 0.708600 ;
    PORT
      LAYER Metal2 ;
        RECT 43.480 215.060 43.880 215.460 ;
    END
  END FrameStrobe_O[7]
  PIN FrameStrobe_O[8]
    DIRECTION OUTPUT ;
    USE SIGNAL ;
    ANTENNADIFFAREA 0.708600 ;
    PORT
      LAYER Metal2 ;
        RECT 48.280 215.060 48.680 215.460 ;
    END
  END FrameStrobe_O[8]
  PIN FrameStrobe_O[9]
    DIRECTION OUTPUT ;
    USE SIGNAL ;
    ANTENNADIFFAREA 0.708600 ;
    PORT
      LAYER Metal2 ;
        RECT 53.080 215.060 53.480 215.460 ;
    END
  END FrameStrobe_O[9]
  PIN UserCLK
    DIRECTION INPUT ;
    USE SIGNAL ;
    ANTENNAGATEAREA 1.450800 ;
    PORT
      LAYER Metal2 ;
        RECT 5.080 0.000 5.480 0.400 ;
    END
  END UserCLK
  PIN UserCLKo
    DIRECTION OUTPUT ;
    USE SIGNAL ;
    ANTENNADIFFAREA 0.708600 ;
    PORT
      LAYER Metal2 ;
        RECT 5.080 215.060 5.480 215.460 ;
    END
  END UserCLKo
  PIN VGND
    DIRECTION INOUT ;
    USE GROUND ;
    PORT
      LAYER TopMetal1 ;
        RECT 21.580 0.000 23.780 215.460 ;
    END
    PORT
      LAYER TopMetal1 ;
        RECT 97.180 0.000 99.380 215.460 ;
    END
  END VGND
  PIN VPWR
    DIRECTION INOUT ;
    USE POWER ;
    PORT
      LAYER TopMetal1 ;
        RECT 15.380 0.000 17.580 215.460 ;
    END
    PORT
      LAYER TopMetal1 ;
        RECT 90.980 0.000 93.180 215.460 ;
    END
  END VPWR
  PIN W1END[0]
    DIRECTION INPUT ;
    USE SIGNAL ;
    ANTENNAGATEAREA 0.180700 ;
    PORT
      LAYER Metal3 ;
        RECT 107.120 0.220 107.520 0.620 ;
    END
  END W1END[0]
  PIN W1END[1]
    DIRECTION INPUT ;
    USE SIGNAL ;
    ANTENNAGATEAREA 0.213200 ;
    PORT
      LAYER Metal3 ;
        RECT 107.120 1.900 107.520 2.300 ;
    END
  END W1END[1]
  PIN W1END[2]
    DIRECTION INPUT ;
    USE SIGNAL ;
    ANTENNAGATEAREA 0.213200 ;
    PORT
      LAYER Metal3 ;
        RECT 107.120 3.580 107.520 3.980 ;
    END
  END W1END[2]
  PIN W1END[3]
    DIRECTION INPUT ;
    USE SIGNAL ;
    ANTENNAGATEAREA 0.213200 ;
    PORT
      LAYER Metal3 ;
        RECT 107.120 5.260 107.520 5.660 ;
    END
  END W1END[3]
  PIN W2END[0]
    DIRECTION INPUT ;
    USE SIGNAL ;
    ANTENNAGATEAREA 0.213200 ;
    PORT
      LAYER Metal3 ;
        RECT 107.120 20.380 107.520 20.780 ;
    END
  END W2END[0]
  PIN W2END[1]
    DIRECTION INPUT ;
    USE SIGNAL ;
    ANTENNAGATEAREA 0.213200 ;
    PORT
      LAYER Metal3 ;
        RECT 107.120 22.060 107.520 22.460 ;
    END
  END W2END[1]
  PIN W2END[2]
    DIRECTION INPUT ;
    USE SIGNAL ;
    ANTENNAGATEAREA 0.213200 ;
    PORT
      LAYER Metal3 ;
        RECT 107.120 23.740 107.520 24.140 ;
    END
  END W2END[2]
  PIN W2END[3]
    DIRECTION INPUT ;
    USE SIGNAL ;
    ANTENNAGATEAREA 0.213200 ;
    PORT
      LAYER Metal3 ;
        RECT 107.120 25.420 107.520 25.820 ;
    END
  END W2END[3]
  PIN W2END[4]
    DIRECTION INPUT ;
    USE SIGNAL ;
    ANTENNAGATEAREA 0.213200 ;
    PORT
      LAYER Metal3 ;
        RECT 107.120 27.100 107.520 27.500 ;
    END
  END W2END[4]
  PIN W2END[5]
    DIRECTION INPUT ;
    USE SIGNAL ;
    ANTENNAGATEAREA 0.213200 ;
    PORT
      LAYER Metal3 ;
        RECT 107.120 28.780 107.520 29.180 ;
    END
  END W2END[5]
  PIN W2END[6]
    DIRECTION INPUT ;
    USE SIGNAL ;
    ANTENNAGATEAREA 0.213200 ;
    PORT
      LAYER Metal3 ;
        RECT 107.120 30.460 107.520 30.860 ;
    END
  END W2END[6]
  PIN W2END[7]
    DIRECTION INPUT ;
    USE SIGNAL ;
    ANTENNAGATEAREA 0.180700 ;
    PORT
      LAYER Metal3 ;
        RECT 107.120 32.140 107.520 32.540 ;
    END
  END W2END[7]
  PIN W2MID[0]
    DIRECTION INPUT ;
    USE SIGNAL ;
    ANTENNAGATEAREA 0.213200 ;
    PORT
      LAYER Metal3 ;
        RECT 107.120 6.940 107.520 7.340 ;
    END
  END W2MID[0]
  PIN W2MID[1]
    DIRECTION INPUT ;
    USE SIGNAL ;
    ANTENNAGATEAREA 0.213200 ;
    PORT
      LAYER Metal3 ;
        RECT 107.120 8.620 107.520 9.020 ;
    END
  END W2MID[1]
  PIN W2MID[2]
    DIRECTION INPUT ;
    USE SIGNAL ;
    ANTENNAGATEAREA 0.213200 ;
    PORT
      LAYER Metal3 ;
        RECT 107.120 10.300 107.520 10.700 ;
    END
  END W2MID[2]
  PIN W2MID[3]
    DIRECTION INPUT ;
    USE SIGNAL ;
    ANTENNAGATEAREA 0.213200 ;
    PORT
      LAYER Metal3 ;
        RECT 107.120 11.980 107.520 12.380 ;
    END
  END W2MID[3]
  PIN W2MID[4]
    DIRECTION INPUT ;
    USE SIGNAL ;
    ANTENNAGATEAREA 0.213200 ;
    PORT
      LAYER Metal3 ;
        RECT 107.120 13.660 107.520 14.060 ;
    END
  END W2MID[4]
  PIN W2MID[5]
    DIRECTION INPUT ;
    USE SIGNAL ;
    ANTENNAGATEAREA 0.213200 ;
    PORT
      LAYER Metal3 ;
        RECT 107.120 15.340 107.520 15.740 ;
    END
  END W2MID[5]
  PIN W2MID[6]
    DIRECTION INPUT ;
    USE SIGNAL ;
    ANTENNAGATEAREA 0.213200 ;
    PORT
      LAYER Metal3 ;
        RECT 107.120 17.020 107.520 17.420 ;
    END
  END W2MID[6]
  PIN W2MID[7]
    DIRECTION INPUT ;
    USE SIGNAL ;
    ANTENNAGATEAREA 0.213200 ;
    PORT
      LAYER Metal3 ;
        RECT 107.120 18.700 107.520 19.100 ;
    END
  END W2MID[7]
  PIN W6END[0]
    DIRECTION INPUT ;
    USE SIGNAL ;
    ANTENNAGATEAREA 0.213200 ;
    PORT
      LAYER Metal3 ;
        RECT 107.120 60.700 107.520 61.100 ;
    END
  END W6END[0]
  PIN W6END[10]
    DIRECTION INPUT ;
    USE SIGNAL ;
    ANTENNAGATEAREA 0.180700 ;
    PORT
      LAYER Metal3 ;
        RECT 107.120 77.500 107.520 77.900 ;
    END
  END W6END[10]
  PIN W6END[11]
    DIRECTION INPUT ;
    USE SIGNAL ;
    ANTENNAGATEAREA 0.180700 ;
    PORT
      LAYER Metal3 ;
        RECT 107.120 79.180 107.520 79.580 ;
    END
  END W6END[11]
  PIN W6END[1]
    DIRECTION INPUT ;
    USE SIGNAL ;
    ANTENNAGATEAREA 0.213200 ;
    PORT
      LAYER Metal3 ;
        RECT 107.120 62.380 107.520 62.780 ;
    END
  END W6END[1]
  PIN W6END[2]
    DIRECTION INPUT ;
    USE SIGNAL ;
    ANTENNAGATEAREA 0.213200 ;
    PORT
      LAYER Metal3 ;
        RECT 107.120 64.060 107.520 64.460 ;
    END
  END W6END[2]
  PIN W6END[3]
    DIRECTION INPUT ;
    USE SIGNAL ;
    ANTENNAGATEAREA 0.213200 ;
    PORT
      LAYER Metal3 ;
        RECT 107.120 65.740 107.520 66.140 ;
    END
  END W6END[3]
  PIN W6END[4]
    DIRECTION INPUT ;
    USE SIGNAL ;
    ANTENNAGATEAREA 0.213200 ;
    PORT
      LAYER Metal3 ;
        RECT 107.120 67.420 107.520 67.820 ;
    END
  END W6END[4]
  PIN W6END[5]
    DIRECTION INPUT ;
    USE SIGNAL ;
    ANTENNAGATEAREA 0.213200 ;
    PORT
      LAYER Metal3 ;
        RECT 107.120 69.100 107.520 69.500 ;
    END
  END W6END[5]
  PIN W6END[6]
    DIRECTION INPUT ;
    USE SIGNAL ;
    ANTENNAGATEAREA 0.213200 ;
    PORT
      LAYER Metal3 ;
        RECT 107.120 70.780 107.520 71.180 ;
    END
  END W6END[6]
  PIN W6END[7]
    DIRECTION INPUT ;
    USE SIGNAL ;
    ANTENNAGATEAREA 0.213200 ;
    PORT
      LAYER Metal3 ;
        RECT 107.120 72.460 107.520 72.860 ;
    END
  END W6END[7]
  PIN W6END[8]
    DIRECTION INPUT ;
    USE SIGNAL ;
    ANTENNAGATEAREA 0.180700 ;
    PORT
      LAYER Metal3 ;
        RECT 107.120 74.140 107.520 74.540 ;
    END
  END W6END[8]
  PIN W6END[9]
    DIRECTION INPUT ;
    USE SIGNAL ;
    ANTENNAGATEAREA 0.180700 ;
    PORT
      LAYER Metal3 ;
        RECT 107.120 75.820 107.520 76.220 ;
    END
  END W6END[9]
  PIN WW4END[0]
    DIRECTION INPUT ;
    USE SIGNAL ;
    ANTENNAGATEAREA 0.180700 ;
    PORT
      LAYER Metal3 ;
        RECT 107.120 33.820 107.520 34.220 ;
    END
  END WW4END[0]
  PIN WW4END[10]
    DIRECTION INPUT ;
    USE SIGNAL ;
    ANTENNAGATEAREA 0.180700 ;
    PORT
      LAYER Metal3 ;
        RECT 107.120 50.620 107.520 51.020 ;
    END
  END WW4END[10]
  PIN WW4END[11]
    DIRECTION INPUT ;
    USE SIGNAL ;
    ANTENNAGATEAREA 0.180700 ;
    PORT
      LAYER Metal3 ;
        RECT 107.120 52.300 107.520 52.700 ;
    END
  END WW4END[11]
  PIN WW4END[12]
    DIRECTION INPUT ;
    USE SIGNAL ;
    ANTENNAGATEAREA 0.180700 ;
    PORT
      LAYER Metal3 ;
        RECT 107.120 53.980 107.520 54.380 ;
    END
  END WW4END[12]
  PIN WW4END[13]
    DIRECTION INPUT ;
    USE SIGNAL ;
    ANTENNAGATEAREA 0.180700 ;
    PORT
      LAYER Metal3 ;
        RECT 107.120 55.660 107.520 56.060 ;
    END
  END WW4END[13]
  PIN WW4END[14]
    DIRECTION INPUT ;
    USE SIGNAL ;
    ANTENNAGATEAREA 0.180700 ;
    PORT
      LAYER Metal3 ;
        RECT 107.120 57.340 107.520 57.740 ;
    END
  END WW4END[14]
  PIN WW4END[15]
    DIRECTION INPUT ;
    USE SIGNAL ;
    ANTENNAGATEAREA 0.180700 ;
    PORT
      LAYER Metal3 ;
        RECT 107.120 59.020 107.520 59.420 ;
    END
  END WW4END[15]
  PIN WW4END[1]
    DIRECTION INPUT ;
    USE SIGNAL ;
    ANTENNAGATEAREA 0.213200 ;
    PORT
      LAYER Metal3 ;
        RECT 107.120 35.500 107.520 35.900 ;
    END
  END WW4END[1]
  PIN WW4END[2]
    DIRECTION INPUT ;
    USE SIGNAL ;
    ANTENNAGATEAREA 0.180700 ;
    PORT
      LAYER Metal3 ;
        RECT 107.120 37.180 107.520 37.580 ;
    END
  END WW4END[2]
  PIN WW4END[3]
    DIRECTION INPUT ;
    USE SIGNAL ;
    ANTENNAGATEAREA 0.180700 ;
    PORT
      LAYER Metal3 ;
        RECT 107.120 38.860 107.520 39.260 ;
    END
  END WW4END[3]
  PIN WW4END[4]
    DIRECTION INPUT ;
    USE SIGNAL ;
    ANTENNAGATEAREA 0.180700 ;
    PORT
      LAYER Metal3 ;
        RECT 107.120 40.540 107.520 40.940 ;
    END
  END WW4END[4]
  PIN WW4END[5]
    DIRECTION INPUT ;
    USE SIGNAL ;
    ANTENNAGATEAREA 0.213200 ;
    PORT
      LAYER Metal3 ;
        RECT 107.120 42.220 107.520 42.620 ;
    END
  END WW4END[5]
  PIN WW4END[6]
    DIRECTION INPUT ;
    USE SIGNAL ;
    ANTENNAGATEAREA 0.180700 ;
    PORT
      LAYER Metal3 ;
        RECT 107.120 43.900 107.520 44.300 ;
    END
  END WW4END[6]
  PIN WW4END[7]
    DIRECTION INPUT ;
    USE SIGNAL ;
    ANTENNAGATEAREA 0.180700 ;
    PORT
      LAYER Metal3 ;
        RECT 107.120 45.580 107.520 45.980 ;
    END
  END WW4END[7]
  PIN WW4END[8]
    DIRECTION INPUT ;
    USE SIGNAL ;
    ANTENNAGATEAREA 0.180700 ;
    PORT
      LAYER Metal3 ;
        RECT 107.120 47.260 107.520 47.660 ;
    END
  END WW4END[8]
  PIN WW4END[9]
    DIRECTION INPUT ;
    USE SIGNAL ;
    ANTENNAGATEAREA 0.180700 ;
    PORT
      LAYER Metal3 ;
        RECT 107.120 48.940 107.520 49.340 ;
    END
  END WW4END[9]
  OBS
      LAYER GatPoly ;
        RECT 2.880 3.630 104.640 211.830 ;
      LAYER Metal1 ;
        RECT 2.880 3.560 104.640 211.900 ;
      LAYER Metal2 ;
        RECT 0.375 214.850 4.870 215.060 ;
        RECT 5.690 214.850 9.670 215.060 ;
        RECT 10.490 214.850 14.470 215.060 ;
        RECT 15.290 214.850 19.270 215.060 ;
        RECT 20.090 214.850 24.070 215.060 ;
        RECT 24.890 214.850 28.870 215.060 ;
        RECT 29.690 214.850 33.670 215.060 ;
        RECT 34.490 214.850 38.470 215.060 ;
        RECT 39.290 214.850 43.270 215.060 ;
        RECT 44.090 214.850 48.070 215.060 ;
        RECT 48.890 214.850 52.870 215.060 ;
        RECT 53.690 214.850 57.670 215.060 ;
        RECT 58.490 214.850 62.470 215.060 ;
        RECT 63.290 214.850 67.270 215.060 ;
        RECT 68.090 214.850 72.070 215.060 ;
        RECT 72.890 214.850 76.870 215.060 ;
        RECT 77.690 214.850 81.670 215.060 ;
        RECT 82.490 214.850 86.470 215.060 ;
        RECT 87.290 214.850 91.270 215.060 ;
        RECT 92.090 214.850 96.070 215.060 ;
        RECT 96.890 214.850 100.870 215.060 ;
        RECT 101.690 214.850 107.145 215.060 ;
        RECT 0.375 0.610 107.145 214.850 ;
        RECT 0.375 0.275 4.870 0.610 ;
        RECT 5.690 0.275 9.670 0.610 ;
        RECT 10.490 0.275 14.470 0.610 ;
        RECT 15.290 0.275 19.270 0.610 ;
        RECT 20.090 0.275 24.070 0.610 ;
        RECT 24.890 0.275 28.870 0.610 ;
        RECT 29.690 0.275 33.670 0.610 ;
        RECT 34.490 0.275 38.470 0.610 ;
        RECT 39.290 0.275 43.270 0.610 ;
        RECT 44.090 0.275 48.070 0.610 ;
        RECT 48.890 0.275 52.870 0.610 ;
        RECT 53.690 0.275 57.670 0.610 ;
        RECT 58.490 0.275 62.470 0.610 ;
        RECT 63.290 0.275 67.270 0.610 ;
        RECT 68.090 0.275 72.070 0.610 ;
        RECT 72.890 0.275 76.870 0.610 ;
        RECT 77.690 0.275 81.670 0.610 ;
        RECT 82.490 0.275 86.470 0.610 ;
        RECT 87.290 0.275 91.270 0.610 ;
        RECT 92.090 0.275 96.070 0.610 ;
        RECT 96.890 0.275 100.870 0.610 ;
        RECT 101.690 0.275 107.145 0.610 ;
      LAYER Metal3 ;
        RECT 0.335 213.370 106.910 213.880 ;
        RECT 0.335 212.510 107.185 213.370 ;
        RECT 0.335 211.690 106.910 212.510 ;
        RECT 0.335 210.830 107.185 211.690 ;
        RECT 0.335 210.010 106.910 210.830 ;
        RECT 0.335 209.150 107.185 210.010 ;
        RECT 0.335 208.330 106.910 209.150 ;
        RECT 0.335 207.470 107.185 208.330 ;
        RECT 0.335 206.650 106.910 207.470 ;
        RECT 0.335 205.790 107.185 206.650 ;
        RECT 0.335 204.970 106.910 205.790 ;
        RECT 0.335 204.110 107.185 204.970 ;
        RECT 0.335 203.290 106.910 204.110 ;
        RECT 0.335 202.430 107.185 203.290 ;
        RECT 0.335 201.610 106.910 202.430 ;
        RECT 0.335 200.750 107.185 201.610 ;
        RECT 0.610 199.930 106.910 200.750 ;
        RECT 0.335 199.070 107.185 199.930 ;
        RECT 0.335 198.250 106.910 199.070 ;
        RECT 0.335 197.390 107.185 198.250 ;
        RECT 0.335 196.570 106.910 197.390 ;
        RECT 0.335 195.710 107.185 196.570 ;
        RECT 0.610 194.890 106.910 195.710 ;
        RECT 0.335 194.030 107.185 194.890 ;
        RECT 0.335 193.210 106.910 194.030 ;
        RECT 0.335 192.350 107.185 193.210 ;
        RECT 0.335 191.530 106.910 192.350 ;
        RECT 0.335 190.670 107.185 191.530 ;
        RECT 0.610 189.850 106.910 190.670 ;
        RECT 0.335 188.990 107.185 189.850 ;
        RECT 0.335 188.170 106.910 188.990 ;
        RECT 0.335 187.310 107.185 188.170 ;
        RECT 0.335 186.490 106.910 187.310 ;
        RECT 0.335 185.630 107.185 186.490 ;
        RECT 0.610 184.810 106.910 185.630 ;
        RECT 0.335 183.950 107.185 184.810 ;
        RECT 0.335 183.130 106.910 183.950 ;
        RECT 0.335 182.270 107.185 183.130 ;
        RECT 0.335 181.450 106.910 182.270 ;
        RECT 0.335 180.590 107.185 181.450 ;
        RECT 0.610 179.770 106.910 180.590 ;
        RECT 0.335 178.910 107.185 179.770 ;
        RECT 0.335 178.090 106.910 178.910 ;
        RECT 0.335 177.230 107.185 178.090 ;
        RECT 0.335 176.410 106.910 177.230 ;
        RECT 0.335 175.550 107.185 176.410 ;
        RECT 0.610 174.730 106.910 175.550 ;
        RECT 0.335 173.870 107.185 174.730 ;
        RECT 0.335 173.050 106.910 173.870 ;
        RECT 0.335 172.190 107.185 173.050 ;
        RECT 0.335 171.370 106.910 172.190 ;
        RECT 0.335 170.510 107.185 171.370 ;
        RECT 0.610 169.690 106.910 170.510 ;
        RECT 0.335 168.830 107.185 169.690 ;
        RECT 0.335 168.010 106.910 168.830 ;
        RECT 0.335 167.150 107.185 168.010 ;
        RECT 0.335 166.330 106.910 167.150 ;
        RECT 0.335 165.470 107.185 166.330 ;
        RECT 0.610 164.650 106.910 165.470 ;
        RECT 0.335 163.790 107.185 164.650 ;
        RECT 0.335 162.970 106.910 163.790 ;
        RECT 0.335 162.110 107.185 162.970 ;
        RECT 0.335 161.290 106.910 162.110 ;
        RECT 0.335 160.430 107.185 161.290 ;
        RECT 0.610 159.610 106.910 160.430 ;
        RECT 0.335 158.750 107.185 159.610 ;
        RECT 0.335 157.930 106.910 158.750 ;
        RECT 0.335 157.070 107.185 157.930 ;
        RECT 0.335 156.250 106.910 157.070 ;
        RECT 0.335 155.390 107.185 156.250 ;
        RECT 0.610 154.570 106.910 155.390 ;
        RECT 0.335 153.710 107.185 154.570 ;
        RECT 0.335 152.890 106.910 153.710 ;
        RECT 0.335 152.030 107.185 152.890 ;
        RECT 0.335 151.210 106.910 152.030 ;
        RECT 0.335 150.350 107.185 151.210 ;
        RECT 0.610 149.530 106.910 150.350 ;
        RECT 0.335 148.670 107.185 149.530 ;
        RECT 0.335 147.850 106.910 148.670 ;
        RECT 0.335 146.990 107.185 147.850 ;
        RECT 0.335 146.170 106.910 146.990 ;
        RECT 0.335 145.310 107.185 146.170 ;
        RECT 0.610 144.490 106.910 145.310 ;
        RECT 0.335 143.630 107.185 144.490 ;
        RECT 0.335 142.810 106.910 143.630 ;
        RECT 0.335 141.950 107.185 142.810 ;
        RECT 0.335 141.130 106.910 141.950 ;
        RECT 0.335 140.270 107.185 141.130 ;
        RECT 0.610 139.450 106.910 140.270 ;
        RECT 0.335 138.590 107.185 139.450 ;
        RECT 0.335 137.770 106.910 138.590 ;
        RECT 0.335 136.910 107.185 137.770 ;
        RECT 0.335 136.090 106.910 136.910 ;
        RECT 0.335 135.230 107.185 136.090 ;
        RECT 0.610 134.410 106.910 135.230 ;
        RECT 0.335 133.550 107.185 134.410 ;
        RECT 0.335 132.730 106.910 133.550 ;
        RECT 0.335 131.870 107.185 132.730 ;
        RECT 0.335 131.050 106.910 131.870 ;
        RECT 0.335 130.190 107.185 131.050 ;
        RECT 0.610 129.370 106.910 130.190 ;
        RECT 0.335 128.510 107.185 129.370 ;
        RECT 0.335 127.690 106.910 128.510 ;
        RECT 0.335 126.830 107.185 127.690 ;
        RECT 0.335 126.010 106.910 126.830 ;
        RECT 0.335 125.150 107.185 126.010 ;
        RECT 0.610 124.330 106.910 125.150 ;
        RECT 0.335 123.470 107.185 124.330 ;
        RECT 0.335 122.650 106.910 123.470 ;
        RECT 0.335 121.790 107.185 122.650 ;
        RECT 0.335 120.970 106.910 121.790 ;
        RECT 0.335 120.110 107.185 120.970 ;
        RECT 0.610 119.290 106.910 120.110 ;
        RECT 0.335 118.430 107.185 119.290 ;
        RECT 0.335 117.610 106.910 118.430 ;
        RECT 0.335 116.750 107.185 117.610 ;
        RECT 0.335 115.930 106.910 116.750 ;
        RECT 0.335 115.070 107.185 115.930 ;
        RECT 0.610 114.250 106.910 115.070 ;
        RECT 0.335 113.390 107.185 114.250 ;
        RECT 0.335 112.570 106.910 113.390 ;
        RECT 0.335 111.710 107.185 112.570 ;
        RECT 0.335 110.890 106.910 111.710 ;
        RECT 0.335 110.030 107.185 110.890 ;
        RECT 0.610 109.210 106.910 110.030 ;
        RECT 0.335 108.350 107.185 109.210 ;
        RECT 0.335 107.530 106.910 108.350 ;
        RECT 0.335 106.670 107.185 107.530 ;
        RECT 0.335 105.850 106.910 106.670 ;
        RECT 0.335 104.990 107.185 105.850 ;
        RECT 0.610 104.170 106.910 104.990 ;
        RECT 0.335 103.310 107.185 104.170 ;
        RECT 0.335 102.490 106.910 103.310 ;
        RECT 0.335 101.630 107.185 102.490 ;
        RECT 0.335 100.810 106.910 101.630 ;
        RECT 0.335 99.950 107.185 100.810 ;
        RECT 0.610 99.130 106.910 99.950 ;
        RECT 0.335 98.270 107.185 99.130 ;
        RECT 0.335 97.450 106.910 98.270 ;
        RECT 0.335 96.590 107.185 97.450 ;
        RECT 0.335 95.770 106.910 96.590 ;
        RECT 0.335 94.910 107.185 95.770 ;
        RECT 0.610 94.090 106.910 94.910 ;
        RECT 0.335 93.230 107.185 94.090 ;
        RECT 0.335 92.410 106.910 93.230 ;
        RECT 0.335 91.550 107.185 92.410 ;
        RECT 0.335 90.730 106.910 91.550 ;
        RECT 0.335 89.870 107.185 90.730 ;
        RECT 0.610 89.050 106.910 89.870 ;
        RECT 0.335 88.190 107.185 89.050 ;
        RECT 0.335 87.370 106.910 88.190 ;
        RECT 0.335 86.510 107.185 87.370 ;
        RECT 0.335 85.690 106.910 86.510 ;
        RECT 0.335 84.830 107.185 85.690 ;
        RECT 0.610 84.010 106.910 84.830 ;
        RECT 0.335 83.150 107.185 84.010 ;
        RECT 0.335 82.330 106.910 83.150 ;
        RECT 0.335 81.470 107.185 82.330 ;
        RECT 0.335 80.650 106.910 81.470 ;
        RECT 0.335 79.790 107.185 80.650 ;
        RECT 0.610 78.970 106.910 79.790 ;
        RECT 0.335 78.110 107.185 78.970 ;
        RECT 0.335 77.290 106.910 78.110 ;
        RECT 0.335 76.430 107.185 77.290 ;
        RECT 0.335 75.610 106.910 76.430 ;
        RECT 0.335 74.750 107.185 75.610 ;
        RECT 0.610 73.930 106.910 74.750 ;
        RECT 0.335 73.070 107.185 73.930 ;
        RECT 0.335 72.250 106.910 73.070 ;
        RECT 0.335 71.390 107.185 72.250 ;
        RECT 0.335 70.570 106.910 71.390 ;
        RECT 0.335 69.710 107.185 70.570 ;
        RECT 0.610 68.890 106.910 69.710 ;
        RECT 0.335 68.030 107.185 68.890 ;
        RECT 0.335 67.210 106.910 68.030 ;
        RECT 0.335 66.350 107.185 67.210 ;
        RECT 0.335 65.530 106.910 66.350 ;
        RECT 0.335 64.670 107.185 65.530 ;
        RECT 0.610 63.850 106.910 64.670 ;
        RECT 0.335 62.990 107.185 63.850 ;
        RECT 0.335 62.170 106.910 62.990 ;
        RECT 0.335 61.310 107.185 62.170 ;
        RECT 0.335 60.490 106.910 61.310 ;
        RECT 0.335 59.630 107.185 60.490 ;
        RECT 0.610 58.810 106.910 59.630 ;
        RECT 0.335 57.950 107.185 58.810 ;
        RECT 0.335 57.130 106.910 57.950 ;
        RECT 0.335 56.270 107.185 57.130 ;
        RECT 0.335 55.450 106.910 56.270 ;
        RECT 0.335 54.590 107.185 55.450 ;
        RECT 0.610 53.770 106.910 54.590 ;
        RECT 0.335 52.910 107.185 53.770 ;
        RECT 0.335 52.090 106.910 52.910 ;
        RECT 0.335 51.230 107.185 52.090 ;
        RECT 0.335 50.410 106.910 51.230 ;
        RECT 0.335 49.550 107.185 50.410 ;
        RECT 0.610 48.730 106.910 49.550 ;
        RECT 0.335 47.870 107.185 48.730 ;
        RECT 0.335 47.050 106.910 47.870 ;
        RECT 0.335 46.190 107.185 47.050 ;
        RECT 0.335 45.370 106.910 46.190 ;
        RECT 0.335 44.510 107.185 45.370 ;
        RECT 0.610 43.690 106.910 44.510 ;
        RECT 0.335 42.830 107.185 43.690 ;
        RECT 0.335 42.010 106.910 42.830 ;
        RECT 0.335 41.150 107.185 42.010 ;
        RECT 0.335 40.330 106.910 41.150 ;
        RECT 0.335 39.470 107.185 40.330 ;
        RECT 0.610 38.650 106.910 39.470 ;
        RECT 0.335 37.790 107.185 38.650 ;
        RECT 0.335 36.970 106.910 37.790 ;
        RECT 0.335 36.110 107.185 36.970 ;
        RECT 0.335 35.290 106.910 36.110 ;
        RECT 0.335 34.430 107.185 35.290 ;
        RECT 0.610 33.610 106.910 34.430 ;
        RECT 0.335 32.750 107.185 33.610 ;
        RECT 0.335 31.930 106.910 32.750 ;
        RECT 0.335 31.070 107.185 31.930 ;
        RECT 0.335 30.250 106.910 31.070 ;
        RECT 0.335 29.390 107.185 30.250 ;
        RECT 0.610 28.570 106.910 29.390 ;
        RECT 0.335 27.710 107.185 28.570 ;
        RECT 0.335 26.890 106.910 27.710 ;
        RECT 0.335 26.030 107.185 26.890 ;
        RECT 0.335 25.210 106.910 26.030 ;
        RECT 0.335 24.350 107.185 25.210 ;
        RECT 0.610 23.530 106.910 24.350 ;
        RECT 0.335 22.670 107.185 23.530 ;
        RECT 0.335 21.850 106.910 22.670 ;
        RECT 0.335 20.990 107.185 21.850 ;
        RECT 0.335 20.170 106.910 20.990 ;
        RECT 0.335 19.310 107.185 20.170 ;
        RECT 0.610 18.490 106.910 19.310 ;
        RECT 0.335 17.630 107.185 18.490 ;
        RECT 0.335 16.810 106.910 17.630 ;
        RECT 0.335 15.950 107.185 16.810 ;
        RECT 0.335 15.130 106.910 15.950 ;
        RECT 0.335 14.270 107.185 15.130 ;
        RECT 0.610 13.450 106.910 14.270 ;
        RECT 0.335 12.590 107.185 13.450 ;
        RECT 0.335 11.770 106.910 12.590 ;
        RECT 0.335 10.910 107.185 11.770 ;
        RECT 0.335 10.090 106.910 10.910 ;
        RECT 0.335 9.230 107.185 10.090 ;
        RECT 0.335 8.410 106.910 9.230 ;
        RECT 0.335 7.550 107.185 8.410 ;
        RECT 0.335 6.730 106.910 7.550 ;
        RECT 0.335 5.870 107.185 6.730 ;
        RECT 0.335 5.050 106.910 5.870 ;
        RECT 0.335 4.190 107.185 5.050 ;
        RECT 0.335 3.370 106.910 4.190 ;
        RECT 0.335 2.510 107.185 3.370 ;
        RECT 0.335 1.690 106.910 2.510 ;
        RECT 0.335 0.830 107.185 1.690 ;
        RECT 0.335 0.315 106.910 0.830 ;
      LAYER Metal4 ;
        RECT 3.260 0.275 106.180 211.825 ;
      LAYER Metal5 ;
        RECT 15.515 3.470 99.245 211.990 ;
  END
END W_IO
END LIBRARY

